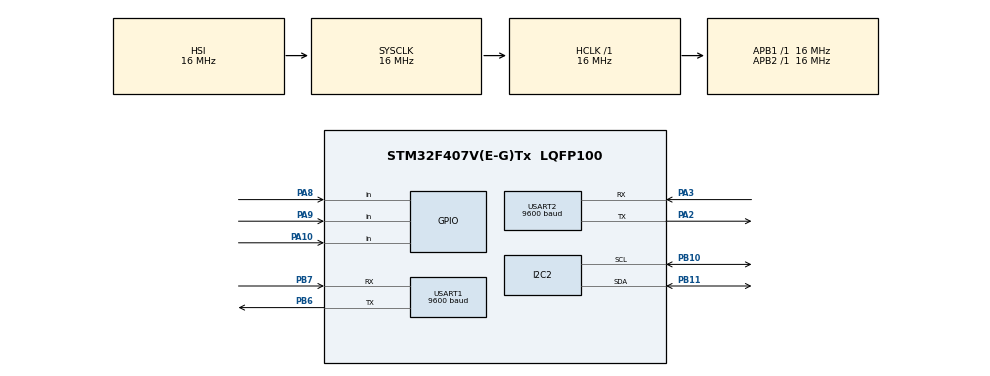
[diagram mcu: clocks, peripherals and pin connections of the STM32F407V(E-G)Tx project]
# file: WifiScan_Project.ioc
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Mcu.Family=STM32F4
Mcu.Name=STM32F407V(E-G)Tx
Mcu.Package=LQFP100
NVIC.PriorityGroup=NVIC_PRIORITYGROUP_4
PA10.Signal=GPIO_Input
PA2.Mode=Asynchronous
PA2.Signal=USART2_TX
PA3.Mode=Asynchronous
PA3.Signal=USART2_RX
PA8.Signal=GPIO_Input
PA9.Signal=GPIO_Input
PB10.Mode=I2C
PB10.Signal=I2C2_SCL
PB11.Mode=I2C
PB11.Signal=I2C2_SDA
PB6.Mode=Asynchronous
PB6.Signal=USART1_TX
PB7.Mode=Asynchronous
PB7.Signal=USART1_RX
ProjectManager.HeapSize=0x200
ProjectManager.StackSize=0x400
ProjectManager.TargetToolchain=STM32CubeIDE
RCC.AHBFreq_Value=16000000
RCC.APB1Freq_Value=16000000
RCC.APB2Freq_Value=16000000
RCC.CortexFreq_Value=16000000
RCC.HSE_VALUE=25000000
RCC.HSI_VALUE=16000000
RCC.LSE_VALUE=32768
RCC.SYSCLKFreq_VALUE=16000000
RCC.VCOOutputFreq_Value=192000000
USART1.BaudRate=9600
USART1.VirtualMode=VM_ASYNC
USART2.BaudRate=9600
USART2.VirtualMode=VM_ASYNC
board=custom

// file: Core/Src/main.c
/* USER CODE BEGIN Header */
/**
  ******************************************************************************
  * @file           : main.c
  * @brief          : Main program body
  ******************************************************************************
  * @attention
  *
  * Copyright (c) 2025 STMicroelectronics.
  * All rights reserved.
  *
  * This software is licensed under terms that can be found in the LICENSE file
  * in the root directory of this software component.
  * If no LICENSE file comes with this software, it is provided AS-IS.
  *
  ******************************************************************************
  */
/* USER CODE END Header */
#include "main.h"

/* USER CODE BEGIN Includes */
#include "oled.h"
#include "string.h"
/* USER CODE END Includes */

/* USER CODE BEGIN PTD */
#define OLED_I2C_ADDR 0x78
/* USER CODE END PTD */

/* USER CODE BEGIN PD */
#define ROW 8
#define COLUMN 32
#define DEBOUNCE_DELAY 200
/* USER CODE END PD */

I2C_HandleTypeDef hi2c2;

UART_HandleTypeDef huart1;
UART_HandleTypeDef huart2;

/* USER CODE BEGIN PV */
char SSID[80];
char ssid[ROW][COLUMN];

int i=0;
int j;
char buffer[20];
int val;
int val2;

int count = 0;
int a;
int b;
int c;
int z=0;
int up_pressed = 0;
int down_pressed = 0;

/* USER CODE END PV */

void SystemClock_Config(void);
static void MX_GPIO_Init(void);
static void MX_I2C2_Init(void);
static void MX_USART2_UART_Init(void);
static void MX_USART1_UART_Init(void);

int main(void)
{

  /* MCU Configuration--------------------------------------------------------*/

  /* Reset of all peripherals, Initializes the Flash interface and the Systick. */
  HAL_Init();

  /* Configure the system clock */
  SystemClock_Config();

  /* Initialize all configured peripherals */
  MX_GPIO_Init();
  MX_I2C2_Init();
  MX_USART2_UART_Init();
  MX_USART1_UART_Init();
  /* USER CODE BEGIN 2 */
  OLED_Init();
  /* USER CODE END 2 */

  /* Infinite loop */
  /* USER CODE BEGIN WHILE */
	while (1)
	{
		HAL_UART_Receive(&huart2, SSID, sizeof(SSID), 1000);

		int val = strcmp(buffer, SSID);

		if (val != 0) {
			OLED_SetCursor(i, 10);
			OLED_PrintString(SSID);
			i++;

			if (count < ROW) {
				strncpy(ssid[count], SSID, COLUMN - 1); // copy outgoing, not buffer
				ssid[count][COLUMN - 1] = '\0';  // Always null-terminate
				count++;
			}

			strcpy(buffer, SSID);  // update buffer after using outgoing
		}

		memset(SSID, 0, sizeof(SSID)); // clear outgoing for next UART receive

		if (i > 7)
			break;

	}

	// Display all SSIDs with initial empty space for cursor
	for (int i = 0; i < count; i++)
	{
	    OLED_SetCursor(i, 4);  // Start at column 1, leave column 0 for cursor
	    OLED_PrintString(" "); // Clear any previous cursor
	    OLED_SetCursor(i, 6);  // Print name with offset
	    OLED_PrintString(ssid[i]);
	}

		  int current_selection = 0;     // Index of current selected SSID
		  int prev_selection = -1;       // Previous index for flicker control
		  int selected = 0;              // Flag to break loop after selection

		  // Navigate and select SSID
		  static uint32_t last_up_time = 0;
		  static uint32_t last_down_time = 0;

		  uint32_t current_time = HAL_GetTick();

		  while (!selected) {
			  current_time = HAL_GetTick();  // <-- Move this here
			  // Check UP button
			  // Check UP button with debounce
			  // UP button debounce
			  // Active LOW button logic
			  if (HAL_GPIO_ReadPin(GPIOA, GPIO_PIN_8) == GPIO_PIN_RESET && !up_pressed)
			  {
			      if (HAL_GetTick() - last_up_time > DEBOUNCE_DELAY) {
			          up_pressed = 1;
			          last_up_time = HAL_GetTick();
			          current_selection = (current_selection > 0) ? current_selection - 1 : count - 1;
			      }
			  }
			  if (HAL_GPIO_ReadPin(GPIOA, GPIO_PIN_8) == GPIO_PIN_SET) {
			      up_pressed = 0;
			  }

			  // Check DOWN button
			  // Check DOWN button with debounce
			  if (HAL_GPIO_ReadPin(GPIOA, GPIO_PIN_9) == GPIO_PIN_RESET && !down_pressed) {
			      if (HAL_GetTick() - last_down_time > DEBOUNCE_DELAY) {
			          down_pressed = 1;
			          last_down_time = HAL_GetTick();
			          current_selection = (current_selection < count - 1) ? current_selection + 1 : 0;
			      }
			  }
			  if (HAL_GPIO_ReadPin(GPIOA, GPIO_PIN_9) == GPIO_PIN_SET) {
			      down_pressed = 0;
			  }

		    // Redraw only when selection changes
			  if (current_selection != prev_selection) {
			      for (int i = 0; i < count; i++) OLED_RangeClear(i, 0, 7);
			      for (int i = 0; i < count; i++) {
			          OLED_SetCursor(i, 8);
			          OLED_PrintString(ssid[i]);
			      }
			      OLED_SetCursor(current_selection, 0);
			      OLED_PrintChar('>');
			      prev_selection = current_selection;
			  }

		    // Add small delay to prevent fast flickering
		    HAL_Delay(100);

		    // Center button logic (Select)
		    static uint32_t last_select_time = 0;
		    static int select_pressed = 0;

		    if (HAL_GPIO_ReadPin(GPIOA, GPIO_PIN_10) == GPIO_PIN_RESET && !select_pressed && (HAL_GetTick() - last_select_time > DEBOUNCE_DELAY))
		    {
		        select_pressed = 1;
		        last_select_time = HAL_GetTick();

		        OLED_Clear();
		        OLED_SetCursor(0, 1);
		        OLED_PrintString(ssid[current_selection]);
		        HAL_UART_Transmit(&huart2, (uint8_t*)ssid[current_selection], strlen(ssid[current_selection]), 1000);
		        selected = 1;
		    }

		    if (HAL_GPIO_ReadPin(GPIOA, GPIO_PIN_10) == GPIO_PIN_SET) {
		        select_pressed = 0;
		    }

		    HAL_Delay(50);
		  }

	  while(1)
	  {
		  HAL_UART_Receive(&huart2,SSID,sizeof(SSID),1000);
		  strcpy(buffer, "Connected successfully!");

		  val2 = strcmp(buffer,SSID);
		  if(val2 == 0)
		  {
			  HAL_UART_Receive(&huart2,SSID,sizeof(SSID),1000);
			  HAL_Delay(1000);
			  HAL_UART_Transmit(&huart1,SSID,sizeof(SSID),1000);
		  }
	  }
	  /* USER CODE END 3 */
	}

void SystemClock_Config(void)
{
  RCC_OscInitTypeDef RCC_OscInitStruct = {0};
  RCC_ClkInitTypeDef RCC_ClkInitStruct = {0};

  /** Configure the main internal regulator output voltage
  */
  __HAL_RCC_PWR_CLK_ENABLE();
  __HAL_PWR_VOLTAGESCALING_CONFIG(PWR_REGULATOR_VOLTAGE_SCALE1);

  /** Initializes the RCC Oscillators according to the specified parameters
  * in the RCC_OscInitTypeDef structure.
  */
  RCC_OscInitStruct.OscillatorType = RCC_OSCILLATORTYPE_HSI;
  RCC_OscInitStruct.HSIState = RCC_HSI_ON;
  RCC_OscInitStruct.HSICalibrationValue = RCC_HSICALIBRATION_DEFAULT;
  RCC_OscInitStruct.PLL.PLLState = RCC_PLL_NONE;
  if (HAL_RCC_OscConfig(&RCC_OscInitStruct) != HAL_OK)
  {
    Error_Handler();
  }

  /** Initializes the CPU, AHB and APB buses clocks
  */
  RCC_ClkInitStruct.ClockType = RCC_CLOCKTYPE_HCLK|RCC_CLOCKTYPE_SYSCLK
                              |RCC_CLOCKTYPE_PCLK1|RCC_CLOCKTYPE_PCLK2;
  RCC_ClkInitStruct.SYSCLKSource = RCC_SYSCLKSOURCE_HSI;
  RCC_ClkInitStruct.AHBCLKDivider = RCC_SYSCLK_DIV1;
  RCC_ClkInitStruct.APB1CLKDivider = RCC_HCLK_DIV1;
  RCC_ClkInitStruct.APB2CLKDivider = RCC_HCLK_DIV1;

  if (HAL_RCC_ClockConfig(&RCC_ClkInitStruct, FLASH_LATENCY_0) != HAL_OK)
  {
    Error_Handler();
  }
}

static void MX_I2C2_Init(void)
{

  hi2c2.Instance = I2C2;
  hi2c2.Init.ClockSpeed = 100000;
  hi2c2.Init.DutyCycle = I2C_DUTYCYCLE_2;
  hi2c2.Init.OwnAddress1 = 0;
  hi2c2.Init.AddressingMode = I2C_ADDRESSINGMODE_7BIT;
  hi2c2.Init.DualAddressMode = I2C_DUALADDRESS_DISABLE;
  hi2c2.Init.OwnAddress2 = 0;
  hi2c2.Init.GeneralCallMode = I2C_GENERALCALL_DISABLE;
  hi2c2.Init.NoStretchMode = I2C_NOSTRETCH_DISABLE;
  if (HAL_I2C_Init(&hi2c2) != HAL_OK)
  {
    Error_Handler();
  }

}

static void MX_USART1_UART_Init(void)
{

  huart1.Instance = USART1;
  huart1.Init.BaudRate = 9600;
  huart1.Init.WordLength = UART_WORDLENGTH_8B;
  huart1.Init.StopBits = UART_STOPBITS_1;
  huart1.Init.Parity = UART_PARITY_NONE;
  huart1.Init.Mode = UART_MODE_TX_RX;
  huart1.Init.HwFlowCtl = UART_HWCONTROL_NONE;
  huart1.Init.OverSampling = UART_OVERSAMPLING_16;
  if (HAL_UART_Init(&huart1) != HAL_OK)
  {
    Error_Handler();
  }

}

static void MX_USART2_UART_Init(void)
{

  huart2.Instance = USART2;
  huart2.Init.BaudRate = 9600;
  huart2.Init.WordLength = UART_WORDLENGTH_8B;
  huart2.Init.StopBits = UART_STOPBITS_1;
  huart2.Init.Parity = UART_PARITY_NONE;
  huart2.Init.Mode = UART_MODE_TX_RX;
  huart2.Init.HwFlowCtl = UART_HWCONTROL_NONE;
  huart2.Init.OverSampling = UART_OVERSAMPLING_16;
  if (HAL_UART_Init(&huart2) != HAL_OK)
  {
    Error_Handler();
  }

}

static void MX_GPIO_Init(void)
{
  GPIO_InitTypeDef GPIO_InitStruct = {0};

  /* GPIO Ports Clock Enable */
  __HAL_RCC_GPIOA_CLK_ENABLE();
  __HAL_RCC_GPIOB_CLK_ENABLE();
  __HAL_RCC_GPIOD_CLK_ENABLE();

  /*Configure GPIO pins : PD10 PD11 PD12 */
  GPIO_InitStruct.Pin = GPIO_PIN_10|GPIO_PIN_11|GPIO_PIN_12;
  GPIO_InitStruct.Mode = GPIO_MODE_INPUT;
  GPIO_InitStruct.Pull = GPIO_NOPULL;
  HAL_GPIO_Init(GPIOD, &GPIO_InitStruct);

}

/* USER CODE BEGIN 4 */
void OLED_SendCommand(uint8_t cmd) {
    uint8_t data[2] = {0x00, cmd};
    HAL_I2C_Master_Transmit(&hi2c2, OLED_I2C_ADDR, data, 2, HAL_MAX_DELAY);
}

void OLED_SendData(uint8_t data) {
    uint8_t buf[2] = {0x40, data};
    HAL_I2C_Master_Transmit(&hi2c2, OLED_I2C_ADDR, buf, 2, HAL_MAX_DELAY);
}
/* USER CODE END 4 */

void Error_Handler(void)
{
  __disable_irq();
  while (1)
  {
  }
}
